###############################################################
#  Generated by:      Cadence Innovus 22.16-s082_1
#  OS:                Linux x86_64(Host ID localhost.localdomain)
#  Generated on:      Sat Nov  7 20:53:31 2026
#  Design:            AMICA_R2_C16_ASIC
#  Command:           write_lef_abstract -extractBlockObs -cutObsMinSpacing -specifyTopLayer metal10 -5.8 -extractBlockPGPinLayers {metal8 metal9} /home/hients/my_design/AMICA_R2_C16_ASIC/INNOVUS/output/09_final_verify_export/runs/20261107_205258_226161_1794059578853175/AMICA_R2_C16_ASIC.lef
###############################################################

VERSION 5.8 ;

BUSBITCHARS "[]" ;
DIVIDERCHAR "/" ;

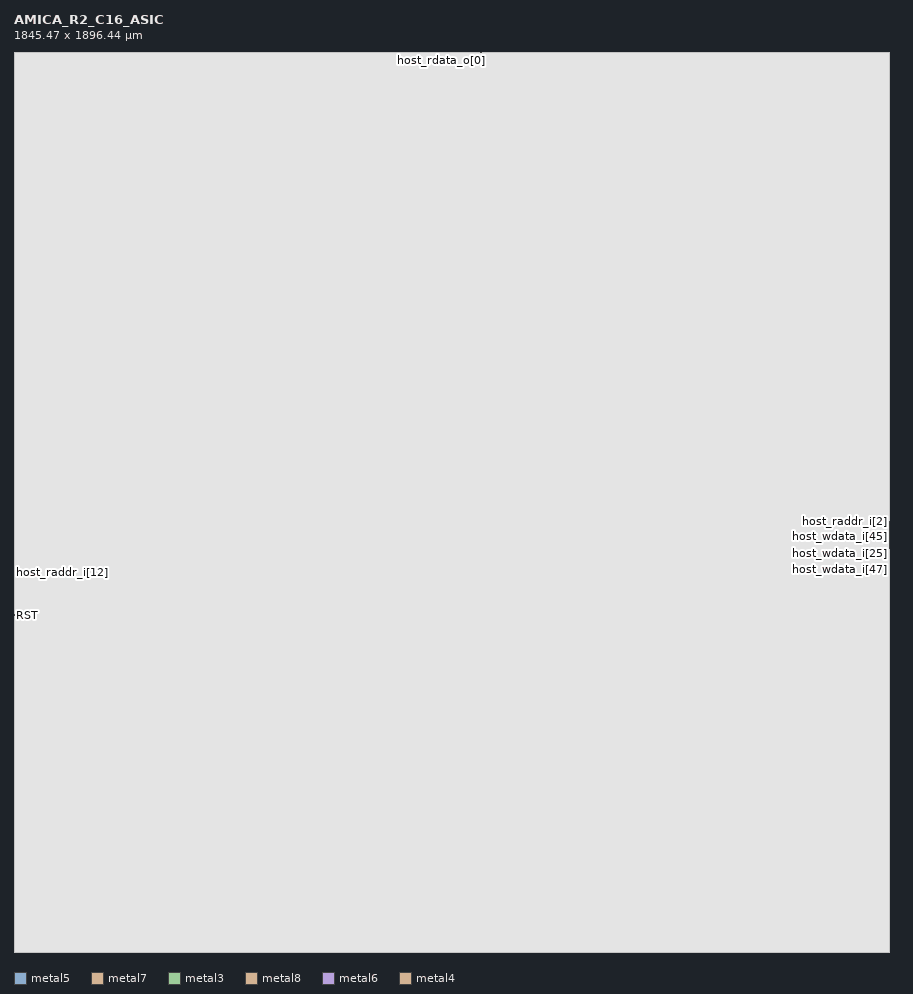
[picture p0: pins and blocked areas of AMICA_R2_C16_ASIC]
MACRO AMICA_R2_C16_ASIC
  CLASS BLOCK ;
  SIZE 1845.470000 BY 1896.440000 ;
  FOREIGN AMICA_R2_C16_ASIC 0.000000 0.000000 ;
  ORIGIN 0 0 ;
  SYMMETRY X Y R90 ;
  PIN CLK
    DIRECTION INPUT ;
    USE SIGNAL ;
    PORT
      LAYER metal5 ;
        RECT 0.000000 699.930000 0.140000 700.070000 ;
    END
  END CLK
  PIN RST
    DIRECTION INPUT ;
    USE SIGNAL ;
    PORT
      LAYER metal5 ;
        RECT 0.000000 710.010000 0.140000 710.150000 ;
    END
  END RST
  PIN host_waddr_i[12]
    DIRECTION INPUT ;
    USE SIGNAL ;
    PORT
      LAYER metal7 ;
        RECT 1845.070000 893.280000 1845.470000 893.680000 ;
    END
  END host_waddr_i[12]
  PIN host_waddr_i[11]
    DIRECTION INPUT ;
    USE SIGNAL ;
    PORT
      LAYER metal5 ;
        RECT 1845.330000 902.090000 1845.470000 902.230000 ;
    END
  END host_waddr_i[11]
  PIN host_waddr_i[10]
    DIRECTION INPUT ;
    USE SIGNAL ;
    PORT
      LAYER metal3 ;
        RECT 1845.400000 904.225000 1845.470000 904.295000 ;
    END
  END host_waddr_i[10]
  PIN host_waddr_i[9]
    DIRECTION INPUT ;
    USE SIGNAL ;
    PORT
      LAYER metal7 ;
        RECT 1845.070000 880.680000 1845.470000 881.080000 ;
    END
  END host_waddr_i[9]
  PIN host_waddr_i[8]
    DIRECTION INPUT ;
    USE SIGNAL ;
    PORT
      LAYER metal5 ;
        RECT 1845.330000 897.890000 1845.470000 898.030000 ;
    END
  END host_waddr_i[8]
  PIN host_waddr_i[7]
    DIRECTION INPUT ;
    USE SIGNAL ;
    PORT
      LAYER metal3 ;
        RECT 1845.400000 902.125000 1845.470000 902.195000 ;
    END
  END host_waddr_i[7]
  PIN host_waddr_i[6]
    DIRECTION INPUT ;
    USE SIGNAL ;
    PORT
      LAYER metal7 ;
        RECT 1845.070000 884.880000 1845.470000 885.280000 ;
    END
  END host_waddr_i[6]
  PIN host_waddr_i[5]
    DIRECTION INPUT ;
    USE SIGNAL ;
    PORT
      LAYER metal5 ;
        RECT 1845.330000 899.290000 1845.470000 899.430000 ;
    END
  END host_waddr_i[5]
  PIN host_waddr_i[4]
    DIRECTION INPUT ;
    USE SIGNAL ;
    PORT
      LAYER metal3 ;
        RECT 1845.400000 902.825000 1845.470000 902.895000 ;
    END
  END host_waddr_i[4]
  PIN host_waddr_i[3]
    DIRECTION INPUT ;
    USE SIGNAL ;
    PORT
      LAYER metal7 ;
        RECT 1845.070000 889.080000 1845.470000 889.480000 ;
    END
  END host_waddr_i[3]
  PIN host_waddr_i[2]
    DIRECTION INPUT ;
    USE SIGNAL ;
    PORT
      LAYER metal5 ;
        RECT 1845.330000 900.690000 1845.470000 900.830000 ;
    END
  END host_waddr_i[2]
  PIN host_waddr_i[1]
    DIRECTION INPUT ;
    USE SIGNAL ;
    PORT
      LAYER metal3 ;
        RECT 1845.400000 903.525000 1845.470000 903.595000 ;
    END
  END host_waddr_i[1]
  PIN host_waddr_i[0]
    DIRECTION INPUT ;
    USE SIGNAL ;
    PORT
      LAYER metal7 ;
        RECT 1845.070000 897.480000 1845.470000 897.880000 ;
    END
  END host_waddr_i[0]
  PIN host_wdata_i[63]
    DIRECTION INPUT ;
    USE SIGNAL ;
    PORT
      LAYER metal7 ;
        RECT 1845.070000 796.680000 1845.470000 797.080000 ;
    END
  END host_wdata_i[63]
  PIN host_wdata_i[62]
    DIRECTION INPUT ;
    USE SIGNAL ;
    PORT
      LAYER metal5 ;
        RECT 1845.330000 869.890000 1845.470000 870.030000 ;
    END
  END host_wdata_i[62]
  PIN host_wdata_i[61]
    DIRECTION INPUT ;
    USE SIGNAL ;
    PORT
      LAYER metal3 ;
        RECT 1845.400000 888.125000 1845.470000 888.195000 ;
    END
  END host_wdata_i[61]
  PIN host_wdata_i[60]
    DIRECTION INPUT ;
    USE SIGNAL ;
    PORT
      LAYER metal7 ;
        RECT 1845.070000 800.880000 1845.470000 801.280000 ;
    END
  END host_wdata_i[60]
  PIN host_wdata_i[59]
    DIRECTION INPUT ;
    USE SIGNAL ;
    PORT
      LAYER metal3 ;
        RECT 1845.400000 888.825000 1845.470000 888.895000 ;
    END
  END host_wdata_i[59]
  PIN host_wdata_i[58]
    DIRECTION INPUT ;
    USE SIGNAL ;
    PORT
      LAYER metal7 ;
        RECT 1845.070000 805.080000 1845.470000 805.480000 ;
    END
  END host_wdata_i[58]
  PIN host_wdata_i[57]
    DIRECTION INPUT ;
    USE SIGNAL ;
    PORT
      LAYER metal5 ;
        RECT 1845.330000 872.690000 1845.470000 872.830000 ;
    END
  END host_wdata_i[57]
  PIN host_wdata_i[56]
    DIRECTION INPUT ;
    USE SIGNAL ;
    PORT
      LAYER metal3 ;
        RECT 1845.400000 889.525000 1845.470000 889.595000 ;
    END
  END host_wdata_i[56]
  PIN host_wdata_i[55]
    DIRECTION INPUT ;
    USE SIGNAL ;
    PORT
      LAYER metal7 ;
        RECT 1845.070000 809.280000 1845.470000 809.680000 ;
    END
  END host_wdata_i[55]
  PIN host_wdata_i[54]
    DIRECTION INPUT ;
    USE SIGNAL ;
    PORT
      LAYER metal5 ;
        RECT 1845.330000 874.090000 1845.470000 874.230000 ;
    END
  END host_wdata_i[54]
  PIN host_wdata_i[53]
    DIRECTION INPUT ;
    USE SIGNAL ;
    PORT
      LAYER metal3 ;
        RECT 1845.400000 890.225000 1845.470000 890.295000 ;
    END
  END host_wdata_i[53]
  PIN host_wdata_i[52]
    DIRECTION INPUT ;
    USE SIGNAL ;
    PORT
      LAYER metal7 ;
        RECT 1845.070000 813.480000 1845.470000 813.880000 ;
    END
  END host_wdata_i[52]
  PIN host_wdata_i[51]
    DIRECTION INPUT ;
    USE SIGNAL ;
    PORT
      LAYER metal5 ;
        RECT 1845.330000 875.490000 1845.470000 875.630000 ;
    END
  END host_wdata_i[51]
  PIN host_wdata_i[50]
    DIRECTION INPUT ;
    USE SIGNAL ;
    PORT
      LAYER metal3 ;
        RECT 1845.400000 890.925000 1845.470000 890.995000 ;
    END
  END host_wdata_i[50]
  PIN host_wdata_i[49]
    DIRECTION INPUT ;
    USE SIGNAL ;
    PORT
      LAYER metal5 ;
        RECT 1845.330000 876.890000 1845.470000 877.030000 ;
    END
  END host_wdata_i[49]
  PIN host_wdata_i[48]
    DIRECTION INPUT ;
    USE SIGNAL ;
    PORT
      LAYER metal3 ;
        RECT 1845.400000 891.625000 1845.470000 891.695000 ;
    END
  END host_wdata_i[48]
  PIN host_wdata_i[47]
    DIRECTION INPUT ;
    USE SIGNAL ;
    PORT
      LAYER metal7 ;
        RECT 1845.070000 821.880000 1845.470000 822.280000 ;
    END
  END host_wdata_i[47]
  PIN host_wdata_i[46]
    DIRECTION INPUT ;
    USE SIGNAL ;
    PORT
      LAYER metal5 ;
        RECT 1845.330000 878.290000 1845.470000 878.430000 ;
    END
  END host_wdata_i[46]
  PIN host_wdata_i[45]
    DIRECTION INPUT ;
    USE SIGNAL ;
    PORT
      LAYER metal3 ;
        RECT 1845.400000 892.325000 1845.470000 892.395000 ;
    END
  END host_wdata_i[45]
  PIN host_wdata_i[44]
    DIRECTION INPUT ;
    USE SIGNAL ;
    PORT
      LAYER metal7 ;
        RECT 1845.070000 826.080000 1845.470000 826.480000 ;
    END
  END host_wdata_i[44]
  PIN host_wdata_i[43]
    DIRECTION INPUT ;
    USE SIGNAL ;
    PORT
      LAYER metal5 ;
        RECT 1845.330000 879.690000 1845.470000 879.830000 ;
    END
  END host_wdata_i[43]
  PIN host_wdata_i[42]
    DIRECTION INPUT ;
    USE SIGNAL ;
    PORT
      LAYER metal3 ;
        RECT 1845.400000 893.025000 1845.470000 893.095000 ;
    END
  END host_wdata_i[42]
  PIN host_wdata_i[41]
    DIRECTION INPUT ;
    USE SIGNAL ;
    PORT
      LAYER metal7 ;
        RECT 1845.070000 830.280000 1845.470000 830.680000 ;
    END
  END host_wdata_i[41]
  PIN host_wdata_i[40]
    DIRECTION INPUT ;
    USE SIGNAL ;
    PORT
      LAYER metal5 ;
        RECT 1845.330000 881.090000 1845.470000 881.230000 ;
    END
  END host_wdata_i[40]
  PIN host_wdata_i[39]
    DIRECTION INPUT ;
    USE SIGNAL ;
    PORT
      LAYER metal7 ;
        RECT 1845.070000 834.480000 1845.470000 834.880000 ;
    END
  END host_wdata_i[39]
  PIN host_wdata_i[38]
    DIRECTION INPUT ;
    USE SIGNAL ;
    PORT
      LAYER metal5 ;
        RECT 1845.330000 882.490000 1845.470000 882.630000 ;
    END
  END host_wdata_i[38]
  PIN host_wdata_i[37]
    DIRECTION INPUT ;
    USE SIGNAL ;
    PORT
      LAYER metal3 ;
        RECT 1845.400000 894.425000 1845.470000 894.495000 ;
    END
  END host_wdata_i[37]
  PIN host_wdata_i[36]
    DIRECTION INPUT ;
    USE SIGNAL ;
    PORT
      LAYER metal7 ;
        RECT 1845.070000 838.680000 1845.470000 839.080000 ;
    END
  END host_wdata_i[36]
  PIN host_wdata_i[35]
    DIRECTION INPUT ;
    USE SIGNAL ;
    PORT
      LAYER metal5 ;
        RECT 1845.330000 883.890000 1845.470000 884.030000 ;
    END
  END host_wdata_i[35]
  PIN host_wdata_i[34]
    DIRECTION INPUT ;
    USE SIGNAL ;
    PORT
      LAYER metal3 ;
        RECT 1845.400000 895.125000 1845.470000 895.195000 ;
    END
  END host_wdata_i[34]
  PIN host_wdata_i[33]
    DIRECTION INPUT ;
    USE SIGNAL ;
    PORT
      LAYER metal7 ;
        RECT 1845.070000 842.880000 1845.470000 843.280000 ;
    END
  END host_wdata_i[33]
  PIN host_wdata_i[32]
    DIRECTION INPUT ;
    USE SIGNAL ;
    PORT
      LAYER metal5 ;
        RECT 1845.330000 885.290000 1845.470000 885.430000 ;
    END
  END host_wdata_i[32]
  PIN host_wdata_i[31]
    DIRECTION INPUT ;
    USE SIGNAL ;
    PORT
      LAYER metal3 ;
        RECT 1845.400000 895.825000 1845.470000 895.895000 ;
    END
  END host_wdata_i[31]
  PIN host_wdata_i[30]
    DIRECTION INPUT ;
    USE SIGNAL ;
    PORT
      LAYER metal7 ;
        RECT 1845.070000 847.080000 1845.470000 847.480000 ;
    END
  END host_wdata_i[30]
  PIN host_wdata_i[29]
    DIRECTION INPUT ;
    USE SIGNAL ;
    PORT
      LAYER metal3 ;
        RECT 1845.400000 896.525000 1845.470000 896.595000 ;
    END
  END host_wdata_i[29]
  PIN host_wdata_i[28]
    DIRECTION INPUT ;
    USE SIGNAL ;
    PORT
      LAYER metal7 ;
        RECT 1845.070000 851.280000 1845.470000 851.680000 ;
    END
  END host_wdata_i[28]
  PIN host_wdata_i[27]
    DIRECTION INPUT ;
    USE SIGNAL ;
    PORT
      LAYER metal5 ;
        RECT 1845.330000 888.090000 1845.470000 888.230000 ;
    END
  END host_wdata_i[27]
  PIN host_wdata_i[26]
    DIRECTION INPUT ;
    USE SIGNAL ;
    PORT
      LAYER metal3 ;
        RECT 1845.400000 897.225000 1845.470000 897.295000 ;
    END
  END host_wdata_i[26]
  PIN host_wdata_i[25]
    DIRECTION INPUT ;
    USE SIGNAL ;
    PORT
      LAYER metal7 ;
        RECT 1845.070000 855.480000 1845.470000 855.880000 ;
    END
  END host_wdata_i[25]
  PIN host_wdata_i[24]
    DIRECTION INPUT ;
    USE SIGNAL ;
    PORT
      LAYER metal5 ;
        RECT 1845.330000 889.490000 1845.470000 889.630000 ;
    END
  END host_wdata_i[24]
  PIN host_wdata_i[23]
    DIRECTION INPUT ;
    USE SIGNAL ;
    PORT
      LAYER metal3 ;
        RECT 1845.400000 897.925000 1845.470000 897.995000 ;
    END
  END host_wdata_i[23]
  PIN host_wdata_i[22]
    DIRECTION INPUT ;
    USE SIGNAL ;
    PORT
      LAYER metal7 ;
        RECT 1845.070000 859.680000 1845.470000 860.080000 ;
    END
  END host_wdata_i[22]
  PIN host_wdata_i[21]
    DIRECTION INPUT ;
    USE SIGNAL ;
    PORT
      LAYER metal5 ;
        RECT 1845.330000 890.890000 1845.470000 891.030000 ;
    END
  END host_wdata_i[21]
  PIN host_wdata_i[20]
    DIRECTION INPUT ;
    USE SIGNAL ;
    PORT
      LAYER metal3 ;
        RECT 1845.400000 898.625000 1845.470000 898.695000 ;
    END
  END host_wdata_i[20]
  PIN host_wdata_i[19]
    DIRECTION INPUT ;
    USE SIGNAL ;
    PORT
      LAYER metal5 ;
        RECT 1845.330000 892.290000 1845.470000 892.430000 ;
    END
  END host_wdata_i[19]
  PIN host_wdata_i[18]
    DIRECTION INPUT ;
    USE SIGNAL ;
    PORT
      LAYER metal3 ;
        RECT 1845.400000 899.325000 1845.470000 899.395000 ;
    END
  END host_wdata_i[18]
  PIN host_wdata_i[17]
    DIRECTION INPUT ;
    USE SIGNAL ;
    PORT
      LAYER metal7 ;
        RECT 1845.070000 868.080000 1845.470000 868.480000 ;
    END
  END host_wdata_i[17]
  PIN host_wdata_i[16]
    DIRECTION INPUT ;
    USE SIGNAL ;
    PORT
      LAYER metal5 ;
        RECT 1845.330000 893.690000 1845.470000 893.830000 ;
    END
  END host_wdata_i[16]
  PIN host_wdata_i[15]
    DIRECTION INPUT ;
    USE SIGNAL ;
    PORT
      LAYER metal3 ;
        RECT 1845.400000 900.025000 1845.470000 900.095000 ;
    END
  END host_wdata_i[15]
  PIN host_wdata_i[14]
    DIRECTION INPUT ;
    USE SIGNAL ;
    PORT
      LAYER metal7 ;
        RECT 1845.070000 872.280000 1845.470000 872.680000 ;
    END
  END host_wdata_i[14]
  PIN host_wdata_i[13]
    DIRECTION INPUT ;
    USE SIGNAL ;
    PORT
      LAYER metal5 ;
        RECT 1845.330000 895.090000 1845.470000 895.230000 ;
    END
  END host_wdata_i[13]
  PIN host_wdata_i[12]
    DIRECTION INPUT ;
    USE SIGNAL ;
    PORT
      LAYER metal3 ;
        RECT 1845.400000 900.725000 1845.470000 900.795000 ;
    END
  END host_wdata_i[12]
  PIN host_wdata_i[11]
    DIRECTION INPUT ;
    USE SIGNAL ;
    PORT
      LAYER metal7 ;
        RECT 1845.070000 876.480000 1845.470000 876.880000 ;
    END
  END host_wdata_i[11]
  PIN host_wdata_i[10]
    DIRECTION INPUT ;
    USE SIGNAL ;
    PORT
      LAYER metal5 ;
        RECT 1845.330000 896.490000 1845.470000 896.630000 ;
    END
  END host_wdata_i[10]
  PIN host_wdata_i[9]
    DIRECTION INPUT ;
    USE SIGNAL ;
    PORT
      LAYER metal3 ;
        RECT 1845.400000 886.725000 1845.470000 886.795000 ;
    END
  END host_wdata_i[9]
  PIN host_wdata_i[8]
    DIRECTION INPUT ;
    USE SIGNAL ;
    PORT
      LAYER metal7 ;
        RECT 1845.070000 792.480000 1845.470000 792.880000 ;
    END
  END host_wdata_i[8]
  PIN host_wdata_i[7]
    DIRECTION INPUT ;
    USE SIGNAL ;
    PORT
      LAYER metal5 ;
        RECT 1845.330000 868.490000 1845.470000 868.630000 ;
    END
  END host_wdata_i[7]
  PIN host_wdata_i[6]
    DIRECTION INPUT ;
    USE SIGNAL ;
    PORT
      LAYER metal3 ;
        RECT 1845.400000 887.425000 1845.470000 887.495000 ;
    END
  END host_wdata_i[6]
  PIN host_wdata_i[5]
    DIRECTION INPUT ;
    USE SIGNAL ;
    PORT
      LAYER metal5 ;
        RECT 1845.330000 871.290000 1845.470000 871.430000 ;
    END
  END host_wdata_i[5]
  PIN host_wdata_i[4]
    DIRECTION INPUT ;
    USE SIGNAL ;
    PORT
      LAYER metal7 ;
        RECT 1845.070000 817.680000 1845.470000 818.080000 ;
    END
  END host_wdata_i[4]
  PIN host_wdata_i[3]
    DIRECTION INPUT ;
    USE SIGNAL ;
    PORT
      LAYER metal3 ;
        RECT 1845.400000 893.725000 1845.470000 893.795000 ;
    END
  END host_wdata_i[3]
  PIN host_wdata_i[2]
    DIRECTION INPUT ;
    USE SIGNAL ;
    PORT
      LAYER metal5 ;
        RECT 1845.330000 886.690000 1845.470000 886.830000 ;
    END
  END host_wdata_i[2]
  PIN host_wdata_i[1]
    DIRECTION INPUT ;
    USE SIGNAL ;
    PORT
      LAYER metal7 ;
        RECT 1845.070000 863.880000 1845.470000 864.280000 ;
    END
  END host_wdata_i[1]
  PIN host_wdata_i[0]
    DIRECTION INPUT ;
    USE SIGNAL ;
    PORT
      LAYER metal3 ;
        RECT 1845.400000 901.425000 1845.470000 901.495000 ;
    END
  END host_wdata_i[0]
  PIN host_wvalid_i
    DIRECTION INPUT ;
    USE SIGNAL ;
    PORT
      LAYER metal5 ;
        RECT 1845.330000 867.090000 1845.470000 867.230000 ;
    END
  END host_wvalid_i
  PIN host_raddr_i[12]
    DIRECTION INPUT ;
    USE SIGNAL ;
    PORT
      LAYER metal3 ;
        RECT 0.000000 800.065000 0.070000 800.135000 ;
    END
  END host_raddr_i[12]
  PIN host_raddr_i[11]
    DIRECTION INPUT ;
    USE SIGNAL ;
    PORT
      LAYER metal5 ;
        RECT 0.000000 800.170000 0.140000 800.310000 ;
    END
  END host_raddr_i[11]
  PIN host_raddr_i[10]
    DIRECTION INPUT ;
    USE SIGNAL ;
    PORT
      LAYER metal7 ;
        RECT 0.000000 800.040000 0.400000 800.440000 ;
    END
  END host_raddr_i[10]
  PIN host_raddr_i[9]
    DIRECTION INPUT ;
    USE SIGNAL ;
    PORT
      LAYER metal5 ;
        RECT 1845.330000 903.490000 1845.470000 903.630000 ;
    END
  END host_raddr_i[9]
  PIN host_raddr_i[8]
    DIRECTION INPUT ;
    USE SIGNAL ;
    PORT
      LAYER metal3 ;
        RECT 1845.400000 904.925000 1845.470000 904.995000 ;
    END
  END host_raddr_i[8]
  PIN host_raddr_i[7]
    DIRECTION INPUT ;
    USE SIGNAL ;
    PORT
      LAYER metal7 ;
        RECT 1845.070000 901.680000 1845.470000 902.080000 ;
    END
  END host_raddr_i[7]
  PIN host_raddr_i[6]
    DIRECTION INPUT ;
    USE SIGNAL ;
    PORT
      LAYER metal5 ;
        RECT 1845.330000 904.890000 1845.470000 905.030000 ;
    END
  END host_raddr_i[6]
  PIN host_raddr_i[5]
    DIRECTION INPUT ;
    USE SIGNAL ;
    PORT
      LAYER metal3 ;
        RECT 1845.400000 905.625000 1845.470000 905.695000 ;
    END
  END host_raddr_i[5]
  PIN host_raddr_i[4]
    DIRECTION INPUT ;
    USE SIGNAL ;
    PORT
      LAYER metal7 ;
        RECT 1845.070000 905.880000 1845.470000 906.280000 ;
    END
  END host_raddr_i[4]
  PIN host_raddr_i[3]
    DIRECTION INPUT ;
    USE SIGNAL ;
    PORT
      LAYER metal5 ;
        RECT 1845.330000 906.290000 1845.470000 906.430000 ;
    END
  END host_raddr_i[3]
  PIN host_raddr_i[2]
    DIRECTION INPUT ;
    USE SIGNAL ;
    PORT
      LAYER metal3 ;
        RECT 1845.400000 906.325000 1845.470000 906.395000 ;
    END
  END host_raddr_i[2]
  PIN host_raddr_i[1]
    DIRECTION INPUT ;
    USE SIGNAL ;
    PORT
      LAYER metal3 ;
        RECT 0.000000 800.765000 0.070000 800.835000 ;
    END
  END host_raddr_i[1]
  PIN host_raddr_i[0]
    DIRECTION INPUT ;
    USE SIGNAL ;
    PORT
      LAYER metal5 ;
        RECT 0.000000 801.570000 0.140000 801.710000 ;
    END
  END host_raddr_i[0]
  PIN host_rvalid_i
    DIRECTION INPUT ;
    USE SIGNAL ;
    PORT
      LAYER metal7 ;
        RECT 0.000000 804.240000 0.400000 804.640000 ;
    END
  END host_rvalid_i
  PIN host_rdata_o[63]
    DIRECTION OUTPUT ;
    USE SIGNAL ;
    PORT
      LAYER metal8 ;
        RECT 979.840000 1896.040000 980.240000 1896.440000 ;
    END
  END host_rdata_o[63]
  PIN host_rdata_o[62]
    DIRECTION OUTPUT ;
    USE SIGNAL ;
    PORT
      LAYER metal6 ;
        RECT 926.770000 1896.300000 926.910000 1896.440000 ;
    END
  END host_rdata_o[62]
  PIN host_rdata_o[61]
    DIRECTION OUTPUT ;
    USE SIGNAL ;
    PORT
      LAYER metal4 ;
        RECT 926.770000 1896.300000 926.910000 1896.440000 ;
    END
  END host_rdata_o[61]
  PIN host_rdata_o[60]
    DIRECTION OUTPUT ;
    USE SIGNAL ;
    PORT
      LAYER metal8 ;
        RECT 975.640000 1896.040000 976.040000 1896.440000 ;
    END
  END host_rdata_o[60]
  PIN host_rdata_o[59]
    DIRECTION OUTPUT ;
    USE SIGNAL ;
    PORT
      LAYER metal4 ;
        RECT 925.370000 1896.300000 925.510000 1896.440000 ;
    END
  END host_rdata_o[59]
  PIN host_rdata_o[58]
    DIRECTION OUTPUT ;
    USE SIGNAL ;
    PORT
      LAYER metal8 ;
        RECT 971.440000 1896.040000 971.840000 1896.440000 ;
    END
  END host_rdata_o[58]
  PIN host_rdata_o[57]
    DIRECTION OUTPUT ;
    USE SIGNAL ;
    PORT
      LAYER metal6 ;
        RECT 923.970000 1896.300000 924.110000 1896.440000 ;
    END
  END host_rdata_o[57]
  PIN host_rdata_o[56]
    DIRECTION OUTPUT ;
    USE SIGNAL ;
    PORT
      LAYER metal4 ;
        RECT 923.970000 1896.300000 924.110000 1896.440000 ;
    END
  END host_rdata_o[56]
  PIN host_rdata_o[55]
    DIRECTION OUTPUT ;
    USE SIGNAL ;
    PORT
      LAYER metal8 ;
        RECT 967.240000 1896.040000 967.640000 1896.440000 ;
    END
  END host_rdata_o[55]
  PIN host_rdata_o[54]
    DIRECTION OUTPUT ;
    USE SIGNAL ;
    PORT
      LAYER metal6 ;
        RECT 922.570000 1896.300000 922.710000 1896.440000 ;
    END
  END host_rdata_o[54]
  PIN host_rdata_o[53]
    DIRECTION OUTPUT ;
    USE SIGNAL ;
    PORT
      LAYER metal4 ;
        RECT 922.570000 1896.300000 922.710000 1896.440000 ;
    END
  END host_rdata_o[53]
  PIN host_rdata_o[52]
    DIRECTION OUTPUT ;
    USE SIGNAL ;
    PORT
      LAYER metal8 ;
        RECT 963.040000 1896.040000 963.440000 1896.440000 ;
    END
  END host_rdata_o[52]
  PIN host_rdata_o[51]
    DIRECTION OUTPUT ;
    USE SIGNAL ;
    PORT
      LAYER metal6 ;
        RECT 921.170000 1896.300000 921.310000 1896.440000 ;
    END
  END host_rdata_o[51]
  PIN host_rdata_o[50]
    DIRECTION OUTPUT ;
    USE SIGNAL ;
    PORT
      LAYER metal4 ;
        RECT 921.170000 1896.300000 921.310000 1896.440000 ;
    END
  END host_rdata_o[50]
  PIN host_rdata_o[49]
    DIRECTION OUTPUT ;
    USE SIGNAL ;
    PORT
      LAYER metal6 ;
        RECT 919.770000 1896.300000 919.910000 1896.440000 ;
    END
  END host_rdata_o[49]
  PIN host_rdata_o[48]
    DIRECTION OUTPUT ;
    USE SIGNAL ;
    PORT
      LAYER metal4 ;
        RECT 919.770000 1896.300000 919.910000 1896.440000 ;
    END
  END host_rdata_o[48]
  PIN host_rdata_o[47]
    DIRECTION OUTPUT ;
    USE SIGNAL ;
    PORT
      LAYER metal8 ;
        RECT 954.640000 1896.040000 955.040000 1896.440000 ;
    END
  END host_rdata_o[47]
  PIN host_rdata_o[46]
    DIRECTION OUTPUT ;
    USE SIGNAL ;
    PORT
      LAYER metal6 ;
        RECT 918.370000 1896.300000 918.510000 1896.440000 ;
    END
  END host_rdata_o[46]
  PIN host_rdata_o[45]
    DIRECTION OUTPUT ;
    USE SIGNAL ;
    PORT
      LAYER metal4 ;
        RECT 918.370000 1896.300000 918.510000 1896.440000 ;
    END
  END host_rdata_o[45]
  PIN host_rdata_o[44]
    DIRECTION OUTPUT ;
    USE SIGNAL ;
    PORT
      LAYER metal8 ;
        RECT 950.440000 1896.040000 950.840000 1896.440000 ;
    END
  END host_rdata_o[44]
  PIN host_rdata_o[43]
    DIRECTION OUTPUT ;
    USE SIGNAL ;
    PORT
      LAYER metal6 ;
        RECT 916.970000 1896.300000 917.110000 1896.440000 ;
    END
  END host_rdata_o[43]
  PIN host_rdata_o[42]
    DIRECTION OUTPUT ;
    USE SIGNAL ;
    PORT
      LAYER metal4 ;
        RECT 916.970000 1896.300000 917.110000 1896.440000 ;
    END
  END host_rdata_o[42]
  PIN host_rdata_o[41]
    DIRECTION OUTPUT ;
    USE SIGNAL ;
    PORT
      LAYER metal8 ;
        RECT 946.240000 1896.040000 946.640000 1896.440000 ;
    END
  END host_rdata_o[41]
  PIN host_rdata_o[40]
    DIRECTION OUTPUT ;
    USE SIGNAL ;
    PORT
      LAYER metal6 ;
        RECT 915.570000 1896.300000 915.710000 1896.440000 ;
    END
  END host_rdata_o[40]
  PIN host_rdata_o[39]
    DIRECTION OUTPUT ;
    USE SIGNAL ;
    PORT
      LAYER metal8 ;
        RECT 942.040000 1896.040000 942.440000 1896.440000 ;
    END
  END host_rdata_o[39]
  PIN host_rdata_o[38]
    DIRECTION OUTPUT ;
    USE SIGNAL ;
    PORT
      LAYER metal6 ;
        RECT 914.170000 1896.300000 914.310000 1896.440000 ;
    END
  END host_rdata_o[38]
  PIN host_rdata_o[37]
    DIRECTION OUTPUT ;
    USE SIGNAL ;
    PORT
      LAYER metal4 ;
        RECT 914.170000 1896.300000 914.310000 1896.440000 ;
    END
  END host_rdata_o[37]
  PIN host_rdata_o[36]
    DIRECTION OUTPUT ;
    USE SIGNAL ;
    PORT
      LAYER metal8 ;
        RECT 937.840000 1896.040000 938.240000 1896.440000 ;
    END
  END host_rdata_o[36]
  PIN host_rdata_o[35]
    DIRECTION OUTPUT ;
    USE SIGNAL ;
    PORT
      LAYER metal6 ;
        RECT 912.770000 1896.300000 912.910000 1896.440000 ;
    END
  END host_rdata_o[35]
  PIN host_rdata_o[34]
    DIRECTION OUTPUT ;
    USE SIGNAL ;
    PORT
      LAYER metal4 ;
        RECT 912.770000 1896.300000 912.910000 1896.440000 ;
    END
  END host_rdata_o[34]
  PIN host_rdata_o[33]
    DIRECTION OUTPUT ;
    USE SIGNAL ;
    PORT
      LAYER metal8 ;
        RECT 933.640000 1896.040000 934.040000 1896.440000 ;
    END
  END host_rdata_o[33]
  PIN host_rdata_o[32]
    DIRECTION OUTPUT ;
    USE SIGNAL ;
    PORT
      LAYER metal6 ;
        RECT 911.370000 1896.300000 911.510000 1896.440000 ;
    END
  END host_rdata_o[32]
  PIN host_rdata_o[31]
    DIRECTION OUTPUT ;
    USE SIGNAL ;
    PORT
      LAYER metal4 ;
        RECT 911.370000 1896.300000 911.510000 1896.440000 ;
    END
  END host_rdata_o[31]
  PIN host_rdata_o[30]
    DIRECTION OUTPUT ;
    USE SIGNAL ;
    PORT
      LAYER metal8 ;
        RECT 929.440000 1896.040000 929.840000 1896.440000 ;
    END
  END host_rdata_o[30]
  PIN host_rdata_o[29]
    DIRECTION OUTPUT ;
    USE SIGNAL ;
    PORT
      LAYER metal4 ;
        RECT 909.970000 1896.300000 910.110000 1896.440000 ;
    END
  END host_rdata_o[29]
  PIN host_rdata_o[28]
    DIRECTION OUTPUT ;
    USE SIGNAL ;
    PORT
      LAYER metal8 ;
        RECT 925.240000 1896.040000 925.640000 1896.440000 ;
    END
  END host_rdata_o[28]
  PIN host_rdata_o[27]
    DIRECTION OUTPUT ;
    USE SIGNAL ;
    PORT
      LAYER metal6 ;
        RECT 908.570000 1896.300000 908.710000 1896.440000 ;
    END
  END host_rdata_o[27]
  PIN host_rdata_o[26]
    DIRECTION OUTPUT ;
    USE SIGNAL ;
    PORT
      LAYER metal4 ;
        RECT 908.570000 1896.300000 908.710000 1896.440000 ;
    END
  END host_rdata_o[26]
  PIN host_rdata_o[25]
    DIRECTION OUTPUT ;
    USE SIGNAL ;
    PORT
      LAYER metal8 ;
        RECT 921.040000 1896.040000 921.440000 1896.440000 ;
    END
  END host_rdata_o[25]
  PIN host_rdata_o[24]
    DIRECTION OUTPUT ;
    USE SIGNAL ;
    PORT
      LAYER metal6 ;
        RECT 907.170000 1896.300000 907.310000 1896.440000 ;
    END
  END host_rdata_o[24]
  PIN host_rdata_o[23]
    DIRECTION OUTPUT ;
    USE SIGNAL ;
    PORT
      LAYER metal4 ;
        RECT 907.170000 1896.300000 907.310000 1896.440000 ;
    END
  END host_rdata_o[23]
  PIN host_rdata_o[22]
    DIRECTION OUTPUT ;
    USE SIGNAL ;
    PORT
      LAYER metal8 ;
        RECT 916.840000 1896.040000 917.240000 1896.440000 ;
    END
  END host_rdata_o[22]
  PIN host_rdata_o[21]
    DIRECTION OUTPUT ;
    USE SIGNAL ;
    PORT
      LAYER metal6 ;
        RECT 905.770000 1896.300000 905.910000 1896.440000 ;
    END
  END host_rdata_o[21]
  PIN host_rdata_o[20]
    DIRECTION OUTPUT ;
    USE SIGNAL ;
    PORT
      LAYER metal4 ;
        RECT 905.770000 1896.300000 905.910000 1896.440000 ;
    END
  END host_rdata_o[20]
  PIN host_rdata_o[19]
    DIRECTION OUTPUT ;
    USE SIGNAL ;
    PORT
      LAYER metal6 ;
        RECT 904.370000 1896.300000 904.510000 1896.440000 ;
    END
  END host_rdata_o[19]
  PIN host_rdata_o[18]
    DIRECTION OUTPUT ;
    USE SIGNAL ;
    PORT
      LAYER metal4 ;
        RECT 904.370000 1896.300000 904.510000 1896.440000 ;
    END
  END host_rdata_o[18]
  PIN host_rdata_o[17]
    DIRECTION OUTPUT ;
    USE SIGNAL ;
    PORT
      LAYER metal8 ;
        RECT 908.440000 1896.040000 908.840000 1896.440000 ;
    END
  END host_rdata_o[17]
  PIN host_rdata_o[16]
    DIRECTION OUTPUT ;
    USE SIGNAL ;
    PORT
      LAYER metal6 ;
        RECT 902.970000 1896.300000 903.110000 1896.440000 ;
    END
  END host_rdata_o[16]
  PIN host_rdata_o[15]
    DIRECTION OUTPUT ;
    USE SIGNAL ;
    PORT
      LAYER metal4 ;
        RECT 902.970000 1896.300000 903.110000 1896.440000 ;
    END
  END host_rdata_o[15]
  PIN host_rdata_o[14]
    DIRECTION OUTPUT ;
    USE SIGNAL ;
    PORT
      LAYER metal8 ;
        RECT 904.240000 1896.040000 904.640000 1896.440000 ;
    END
  END host_rdata_o[14]
  PIN host_rdata_o[13]
    DIRECTION OUTPUT ;
    USE SIGNAL ;
    PORT
      LAYER metal6 ;
        RECT 901.570000 1896.300000 901.710000 1896.440000 ;
    END
  END host_rdata_o[13]
  PIN host_rdata_o[12]
    DIRECTION OUTPUT ;
    USE SIGNAL ;
    PORT
      LAYER metal4 ;
        RECT 901.570000 1896.300000 901.710000 1896.440000 ;
    END
  END host_rdata_o[12]
  PIN host_rdata_o[11]
    DIRECTION OUTPUT ;
    USE SIGNAL ;
    PORT
      LAYER metal8 ;
        RECT 900.040000 1896.040000 900.440000 1896.440000 ;
    END
  END host_rdata_o[11]
  PIN host_rdata_o[10]
    DIRECTION OUTPUT ;
    USE SIGNAL ;
    PORT
      LAYER metal6 ;
        RECT 900.170000 1896.300000 900.310000 1896.440000 ;
    END
  END host_rdata_o[10]
  PIN host_rdata_o[9]
    DIRECTION OUTPUT ;
    USE SIGNAL ;
    PORT
      LAYER metal4 ;
        RECT 929.570000 1896.300000 929.710000 1896.440000 ;
    END
  END host_rdata_o[9]
  PIN host_rdata_o[8]
    DIRECTION OUTPUT ;
    USE SIGNAL ;
    PORT
      LAYER metal8 ;
        RECT 984.040000 1896.040000 984.440000 1896.440000 ;
    END
  END host_rdata_o[8]
  PIN host_rdata_o[7]
    DIRECTION OUTPUT ;
    USE SIGNAL ;
    PORT
      LAYER metal6 ;
        RECT 928.170000 1896.300000 928.310000 1896.440000 ;
    END
  END host_rdata_o[7]
  PIN host_rdata_o[6]
    DIRECTION OUTPUT ;
    USE SIGNAL ;
    PORT
      LAYER metal4 ;
        RECT 928.170000 1896.300000 928.310000 1896.440000 ;
    END
  END host_rdata_o[6]
  PIN host_rdata_o[5]
    DIRECTION OUTPUT ;
    USE SIGNAL ;
    PORT
      LAYER metal6 ;
        RECT 925.370000 1896.300000 925.510000 1896.440000 ;
    END
  END host_rdata_o[5]
  PIN host_rdata_o[4]
    DIRECTION OUTPUT ;
    USE SIGNAL ;
    PORT
      LAYER metal8 ;
        RECT 958.840000 1896.040000 959.240000 1896.440000 ;
    END
  END host_rdata_o[4]
  PIN host_rdata_o[3]
    DIRECTION OUTPUT ;
    USE SIGNAL ;
    PORT
      LAYER metal4 ;
        RECT 915.570000 1896.300000 915.710000 1896.440000 ;
    END
  END host_rdata_o[3]
  PIN host_rdata_o[2]
    DIRECTION OUTPUT ;
    USE SIGNAL ;
    PORT
      LAYER metal6 ;
        RECT 909.970000 1896.300000 910.110000 1896.440000 ;
    END
  END host_rdata_o[2]
  PIN host_rdata_o[1]
    DIRECTION OUTPUT ;
    USE SIGNAL ;
    PORT
      LAYER metal8 ;
        RECT 912.640000 1896.040000 913.040000 1896.440000 ;
    END
  END host_rdata_o[1]
  PIN host_rdata_o[0]
    DIRECTION OUTPUT ;
    USE SIGNAL ;
    PORT
      LAYER metal4 ;
        RECT 900.170000 1896.300000 900.310000 1896.440000 ;
    END
  END host_rdata_o[0]
  OBS
    LAYER metal1 ;
      RECT 0.000000 0.000000 1845.470000 1896.440000 ;
    LAYER metal2 ;
      RECT 0.000000 0.000000 1845.470000 1896.440000 ;
    LAYER metal3 ;
      RECT 0.000000 906.465000 1845.470000 1896.440000 ;
      RECT 0.000000 906.255000 1845.330000 906.465000 ;
      RECT 0.000000 905.765000 1845.470000 906.255000 ;
      RECT 0.000000 905.555000 1845.330000 905.765000 ;
      RECT 0.000000 905.065000 1845.470000 905.555000 ;
      RECT 0.000000 904.855000 1845.330000 905.065000 ;
      RECT 0.000000 904.365000 1845.470000 904.855000 ;
      RECT 0.000000 904.155000 1845.330000 904.365000 ;
      RECT 0.000000 903.665000 1845.470000 904.155000 ;
      RECT 0.000000 903.455000 1845.330000 903.665000 ;
      RECT 0.000000 902.965000 1845.470000 903.455000 ;
      RECT 0.000000 902.755000 1845.330000 902.965000 ;
      RECT 0.000000 902.265000 1845.470000 902.755000 ;
      RECT 0.000000 902.055000 1845.330000 902.265000 ;
      RECT 0.000000 901.565000 1845.470000 902.055000 ;
      RECT 0.000000 901.355000 1845.330000 901.565000 ;
      RECT 0.000000 900.865000 1845.470000 901.355000 ;
      RECT 0.000000 900.655000 1845.330000 900.865000 ;
      RECT 0.000000 900.165000 1845.470000 900.655000 ;
      RECT 0.000000 899.955000 1845.330000 900.165000 ;
      RECT 0.000000 899.465000 1845.470000 899.955000 ;
      RECT 0.000000 899.255000 1845.330000 899.465000 ;
      RECT 0.000000 898.765000 1845.470000 899.255000 ;
      RECT 0.000000 898.555000 1845.330000 898.765000 ;
      RECT 0.000000 898.065000 1845.470000 898.555000 ;
      RECT 0.000000 897.855000 1845.330000 898.065000 ;
      RECT 0.000000 897.365000 1845.470000 897.855000 ;
      RECT 0.000000 897.155000 1845.330000 897.365000 ;
      RECT 0.000000 896.665000 1845.470000 897.155000 ;
      RECT 0.000000 896.455000 1845.330000 896.665000 ;
      RECT 0.000000 895.965000 1845.470000 896.455000 ;
      RECT 0.000000 895.755000 1845.330000 895.965000 ;
      RECT 0.000000 895.265000 1845.470000 895.755000 ;
      RECT 0.000000 895.055000 1845.330000 895.265000 ;
      RECT 0.000000 894.565000 1845.470000 895.055000 ;
      RECT 0.000000 894.355000 1845.330000 894.565000 ;
      RECT 0.000000 893.865000 1845.470000 894.355000 ;
      RECT 0.000000 893.655000 1845.330000 893.865000 ;
      RECT 0.000000 893.165000 1845.470000 893.655000 ;
      RECT 0.000000 892.955000 1845.330000 893.165000 ;
      RECT 0.000000 892.465000 1845.470000 892.955000 ;
      RECT 0.000000 892.255000 1845.330000 892.465000 ;
      RECT 0.000000 891.765000 1845.470000 892.255000 ;
      RECT 0.000000 891.555000 1845.330000 891.765000 ;
      RECT 0.000000 891.065000 1845.470000 891.555000 ;
      RECT 0.000000 890.855000 1845.330000 891.065000 ;
      RECT 0.000000 890.365000 1845.470000 890.855000 ;
      RECT 0.000000 890.155000 1845.330000 890.365000 ;
      RECT 0.000000 889.665000 1845.470000 890.155000 ;
      RECT 0.000000 889.455000 1845.330000 889.665000 ;
      RECT 0.000000 888.965000 1845.470000 889.455000 ;
      RECT 0.000000 888.755000 1845.330000 888.965000 ;
      RECT 0.000000 888.265000 1845.470000 888.755000 ;
      RECT 0.000000 888.055000 1845.330000 888.265000 ;
      RECT 0.000000 887.565000 1845.470000 888.055000 ;
      RECT 0.000000 887.355000 1845.330000 887.565000 ;
      RECT 0.000000 886.865000 1845.470000 887.355000 ;
      RECT 0.000000 886.655000 1845.330000 886.865000 ;
      RECT 0.000000 800.905000 1845.470000 886.655000 ;
      RECT 0.140000 800.695000 1845.470000 800.905000 ;
      RECT 0.000000 800.205000 1845.470000 800.695000 ;
      RECT 0.140000 799.995000 1845.470000 800.205000 ;
      RECT 0.000000 0.000000 1845.470000 799.995000 ;
    LAYER metal4 ;
      RECT 929.850000 1896.160000 1845.470000 1896.440000 ;
      RECT 928.450000 1896.160000 929.430000 1896.440000 ;
      RECT 927.050000 1896.160000 928.030000 1896.440000 ;
      RECT 925.650000 1896.160000 926.630000 1896.440000 ;
      RECT 924.250000 1896.160000 925.230000 1896.440000 ;
      RECT 922.850000 1896.160000 923.830000 1896.440000 ;
      RECT 921.450000 1896.160000 922.430000 1896.440000 ;
      RECT 920.050000 1896.160000 921.030000 1896.440000 ;
      RECT 918.650000 1896.160000 919.630000 1896.440000 ;
      RECT 917.250000 1896.160000 918.230000 1896.440000 ;
      RECT 915.850000 1896.160000 916.830000 1896.440000 ;
      RECT 914.450000 1896.160000 915.430000 1896.440000 ;
      RECT 913.050000 1896.160000 914.030000 1896.440000 ;
      RECT 911.650000 1896.160000 912.630000 1896.440000 ;
      RECT 910.250000 1896.160000 911.230000 1896.440000 ;
      RECT 908.850000 1896.160000 909.830000 1896.440000 ;
      RECT 907.450000 1896.160000 908.430000 1896.440000 ;
      RECT 906.050000 1896.160000 907.030000 1896.440000 ;
      RECT 904.650000 1896.160000 905.630000 1896.440000 ;
      RECT 903.250000 1896.160000 904.230000 1896.440000 ;
      RECT 901.850000 1896.160000 902.830000 1896.440000 ;
      RECT 900.450000 1896.160000 901.430000 1896.440000 ;
      RECT 0.000000 1896.160000 900.030000 1896.440000 ;
      RECT 0.000000 0.000000 1845.470000 1896.160000 ;
    LAYER metal5 ;
      RECT 0.000000 906.570000 1845.470000 1896.440000 ;
      RECT 0.000000 906.150000 1845.190000 906.570000 ;
      RECT 0.000000 905.170000 1845.470000 906.150000 ;
      RECT 0.000000 904.750000 1845.190000 905.170000 ;
      RECT 0.000000 903.770000 1845.470000 904.750000 ;
      RECT 0.000000 903.350000 1845.190000 903.770000 ;
      RECT 0.000000 902.370000 1845.470000 903.350000 ;
      RECT 0.000000 901.950000 1845.190000 902.370000 ;
      RECT 0.000000 900.970000 1845.470000 901.950000 ;
      RECT 0.000000 900.550000 1845.190000 900.970000 ;
      RECT 0.000000 899.570000 1845.470000 900.550000 ;
      RECT 0.000000 899.150000 1845.190000 899.570000 ;
      RECT 0.000000 898.170000 1845.470000 899.150000 ;
      RECT 0.000000 897.750000 1845.190000 898.170000 ;
      RECT 0.000000 896.770000 1845.470000 897.750000 ;
      RECT 0.000000 896.350000 1845.190000 896.770000 ;
      RECT 0.000000 895.370000 1845.470000 896.350000 ;
      RECT 0.000000 894.950000 1845.190000 895.370000 ;
      RECT 0.000000 893.970000 1845.470000 894.950000 ;
      RECT 0.000000 893.550000 1845.190000 893.970000 ;
      RECT 0.000000 892.570000 1845.470000 893.550000 ;
      RECT 0.000000 892.150000 1845.190000 892.570000 ;
      RECT 0.000000 891.170000 1845.470000 892.150000 ;
      RECT 0.000000 890.750000 1845.190000 891.170000 ;
      RECT 0.000000 889.770000 1845.470000 890.750000 ;
      RECT 0.000000 889.350000 1845.190000 889.770000 ;
      RECT 0.000000 888.370000 1845.470000 889.350000 ;
      RECT 0.000000 887.950000 1845.190000 888.370000 ;
      RECT 0.000000 886.970000 1845.470000 887.950000 ;
      RECT 0.000000 886.550000 1845.190000 886.970000 ;
      RECT 0.000000 885.570000 1845.470000 886.550000 ;
      RECT 0.000000 885.150000 1845.190000 885.570000 ;
      RECT 0.000000 884.170000 1845.470000 885.150000 ;
      RECT 0.000000 883.750000 1845.190000 884.170000 ;
      RECT 0.000000 882.770000 1845.470000 883.750000 ;
      RECT 0.000000 882.350000 1845.190000 882.770000 ;
      RECT 0.000000 881.370000 1845.470000 882.350000 ;
      RECT 0.000000 880.950000 1845.190000 881.370000 ;
      RECT 0.000000 879.970000 1845.470000 880.950000 ;
      RECT 0.000000 879.550000 1845.190000 879.970000 ;
      RECT 0.000000 878.570000 1845.470000 879.550000 ;
      RECT 0.000000 878.150000 1845.190000 878.570000 ;
      RECT 0.000000 877.170000 1845.470000 878.150000 ;
      RECT 0.000000 876.750000 1845.190000 877.170000 ;
      RECT 0.000000 875.770000 1845.470000 876.750000 ;
      RECT 0.000000 875.350000 1845.190000 875.770000 ;
      RECT 0.000000 874.370000 1845.470000 875.350000 ;
      RECT 0.000000 873.950000 1845.190000 874.370000 ;
      RECT 0.000000 872.970000 1845.470000 873.950000 ;
      RECT 0.000000 872.550000 1845.190000 872.970000 ;
      RECT 0.000000 871.570000 1845.470000 872.550000 ;
      RECT 0.000000 871.150000 1845.190000 871.570000 ;
      RECT 0.000000 870.170000 1845.470000 871.150000 ;
      RECT 0.000000 869.750000 1845.190000 870.170000 ;
      RECT 0.000000 868.770000 1845.470000 869.750000 ;
      RECT 0.000000 868.350000 1845.190000 868.770000 ;
      RECT 0.000000 867.370000 1845.470000 868.350000 ;
      RECT 0.000000 866.950000 1845.190000 867.370000 ;
      RECT 0.000000 801.850000 1845.470000 866.950000 ;
      RECT 0.280000 801.430000 1845.470000 801.850000 ;
      RECT 0.000000 800.450000 1845.470000 801.430000 ;
      RECT 0.280000 800.030000 1845.470000 800.450000 ;
      RECT 0.000000 710.290000 1845.470000 800.030000 ;
      RECT 0.280000 709.870000 1845.470000 710.290000 ;
      RECT 0.000000 700.210000 1845.470000 709.870000 ;
      RECT 0.280000 699.790000 1845.470000 700.210000 ;
      RECT 0.000000 0.000000 1845.470000 699.790000 ;
    LAYER metal6 ;
      RECT 928.450000 1896.160000 1845.470000 1896.440000 ;
      RECT 927.050000 1896.160000 928.030000 1896.440000 ;
      RECT 925.650000 1896.160000 926.630000 1896.440000 ;
      RECT 924.250000 1896.160000 925.230000 1896.440000 ;
      RECT 922.850000 1896.160000 923.830000 1896.440000 ;
      RECT 921.450000 1896.160000 922.430000 1896.440000 ;
      RECT 920.050000 1896.160000 921.030000 1896.440000 ;
      RECT 918.650000 1896.160000 919.630000 1896.440000 ;
      RECT 917.250000 1896.160000 918.230000 1896.440000 ;
      RECT 915.850000 1896.160000 916.830000 1896.440000 ;
      RECT 914.450000 1896.160000 915.430000 1896.440000 ;
      RECT 913.050000 1896.160000 914.030000 1896.440000 ;
      RECT 911.650000 1896.160000 912.630000 1896.440000 ;
      RECT 910.250000 1896.160000 911.230000 1896.440000 ;
      RECT 908.850000 1896.160000 909.830000 1896.440000 ;
      RECT 907.450000 1896.160000 908.430000 1896.440000 ;
      RECT 906.050000 1896.160000 907.030000 1896.440000 ;
      RECT 904.650000 1896.160000 905.630000 1896.440000 ;
      RECT 903.250000 1896.160000 904.230000 1896.440000 ;
      RECT 901.850000 1896.160000 902.830000 1896.440000 ;
      RECT 900.450000 1896.160000 901.430000 1896.440000 ;
      RECT 0.000000 1896.160000 900.030000 1896.440000 ;
      RECT 0.000000 0.000000 1845.470000 1896.160000 ;
    LAYER metal7 ;
      RECT 0.000000 906.680000 1845.470000 1896.440000 ;
      RECT 0.000000 905.480000 1844.670000 906.680000 ;
      RECT 0.000000 902.480000 1845.470000 905.480000 ;
      RECT 0.000000 901.280000 1844.670000 902.480000 ;
      RECT 0.000000 898.280000 1845.470000 901.280000 ;
      RECT 0.000000 897.080000 1844.670000 898.280000 ;
      RECT 0.000000 894.080000 1845.470000 897.080000 ;
      RECT 0.000000 892.880000 1844.670000 894.080000 ;
      RECT 0.000000 889.880000 1845.470000 892.880000 ;
      RECT 0.000000 888.680000 1844.670000 889.880000 ;
      RECT 0.000000 885.680000 1845.470000 888.680000 ;
      RECT 0.000000 884.480000 1844.670000 885.680000 ;
      RECT 0.000000 881.480000 1845.470000 884.480000 ;
      RECT 0.000000 880.280000 1844.670000 881.480000 ;
      RECT 0.000000 877.280000 1845.470000 880.280000 ;
      RECT 0.000000 876.080000 1844.670000 877.280000 ;
      RECT 0.000000 873.080000 1845.470000 876.080000 ;
      RECT 0.000000 871.880000 1844.670000 873.080000 ;
      RECT 0.000000 868.880000 1845.470000 871.880000 ;
      RECT 0.000000 867.680000 1844.670000 868.880000 ;
      RECT 0.000000 864.680000 1845.470000 867.680000 ;
      RECT 0.000000 863.480000 1844.670000 864.680000 ;
      RECT 0.000000 860.480000 1845.470000 863.480000 ;
      RECT 0.000000 859.280000 1844.670000 860.480000 ;
      RECT 0.000000 856.280000 1845.470000 859.280000 ;
      RECT 0.000000 855.080000 1844.670000 856.280000 ;
      RECT 0.000000 852.080000 1845.470000 855.080000 ;
      RECT 0.000000 850.880000 1844.670000 852.080000 ;
      RECT 0.000000 847.880000 1845.470000 850.880000 ;
      RECT 0.000000 846.680000 1844.670000 847.880000 ;
      RECT 0.000000 843.680000 1845.470000 846.680000 ;
      RECT 0.000000 842.480000 1844.670000 843.680000 ;
      RECT 0.000000 839.480000 1845.470000 842.480000 ;
      RECT 0.000000 838.280000 1844.670000 839.480000 ;
      RECT 0.000000 835.280000 1845.470000 838.280000 ;
      RECT 0.000000 834.080000 1844.670000 835.280000 ;
      RECT 0.000000 831.080000 1845.470000 834.080000 ;
      RECT 0.000000 829.880000 1844.670000 831.080000 ;
      RECT 0.000000 826.880000 1845.470000 829.880000 ;
      RECT 0.000000 825.680000 1844.670000 826.880000 ;
      RECT 0.000000 822.680000 1845.470000 825.680000 ;
      RECT 0.000000 821.480000 1844.670000 822.680000 ;
      RECT 0.000000 818.480000 1845.470000 821.480000 ;
      RECT 0.000000 817.280000 1844.670000 818.480000 ;
      RECT 0.000000 814.280000 1845.470000 817.280000 ;
      RECT 0.000000 813.080000 1844.670000 814.280000 ;
      RECT 0.000000 810.080000 1845.470000 813.080000 ;
      RECT 0.000000 808.880000 1844.670000 810.080000 ;
      RECT 0.000000 805.880000 1845.470000 808.880000 ;
      RECT 0.000000 805.040000 1844.670000 805.880000 ;
      RECT 0.800000 804.680000 1844.670000 805.040000 ;
      RECT 0.800000 803.840000 1845.470000 804.680000 ;
      RECT 0.000000 801.680000 1845.470000 803.840000 ;
      RECT 0.000000 800.840000 1844.670000 801.680000 ;
      RECT 0.800000 800.480000 1844.670000 800.840000 ;
      RECT 0.800000 799.640000 1845.470000 800.480000 ;
      RECT 0.000000 797.480000 1845.470000 799.640000 ;
      RECT 0.000000 796.280000 1844.670000 797.480000 ;
      RECT 0.000000 793.280000 1845.470000 796.280000 ;
      RECT 0.000000 792.080000 1844.670000 793.280000 ;
      RECT 0.000000 0.000000 1845.470000 792.080000 ;
    LAYER metal8 ;
      RECT 984.840000 1895.640000 1845.470000 1896.440000 ;
      RECT 980.640000 1895.640000 983.640000 1896.440000 ;
      RECT 976.440000 1895.640000 979.440000 1896.440000 ;
      RECT 972.240000 1895.640000 975.240000 1896.440000 ;
      RECT 968.040000 1895.640000 971.040000 1896.440000 ;
      RECT 963.840000 1895.640000 966.840000 1896.440000 ;
      RECT 959.640000 1895.640000 962.640000 1896.440000 ;
      RECT 955.440000 1895.640000 958.440000 1896.440000 ;
      RECT 951.240000 1895.640000 954.240000 1896.440000 ;
      RECT 947.040000 1895.640000 950.040000 1896.440000 ;
      RECT 942.840000 1895.640000 945.840000 1896.440000 ;
      RECT 938.640000 1895.640000 941.640000 1896.440000 ;
      RECT 934.440000 1895.640000 937.440000 1896.440000 ;
      RECT 930.240000 1895.640000 933.240000 1896.440000 ;
      RECT 926.040000 1895.640000 929.040000 1896.440000 ;
      RECT 921.840000 1895.640000 924.840000 1896.440000 ;
      RECT 917.640000 1895.640000 920.640000 1896.440000 ;
      RECT 913.440000 1895.640000 916.440000 1896.440000 ;
      RECT 909.240000 1895.640000 912.240000 1896.440000 ;
      RECT 905.040000 1895.640000 908.040000 1896.440000 ;
      RECT 900.840000 1895.640000 903.840000 1896.440000 ;
      RECT 0.000000 1895.640000 899.640000 1896.440000 ;
      RECT 0.000000 0.000000 1845.470000 1895.640000 ;
    LAYER metal9 ;
      RECT 0.000000 0.000000 1845.470000 1896.440000 ;
    LAYER metal10 ;
      RECT 0.000000 0.000000 1845.470000 1896.440000 ;
  END
END AMICA_R2_C16_ASIC

END LIBRARY
